One B-rep face of a CAD part: STEP entity #1964.
In plain terms, the planar face has unit normal (0, -1, 0).
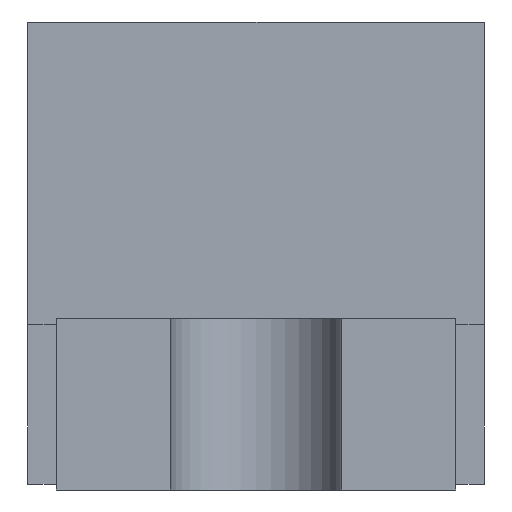
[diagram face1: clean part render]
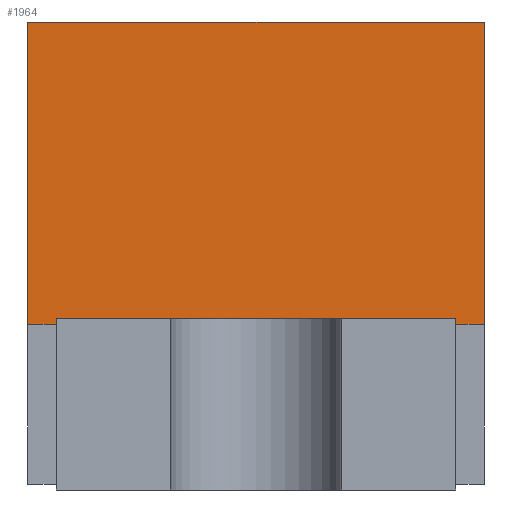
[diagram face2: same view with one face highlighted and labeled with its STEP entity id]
Its self-contained STEP definition (entity closure, numbers rounded to 3 decimals):
#1964 = ADVANCED_FACE('',(#1965),#1979,.F.);
#1965 = FACE_BOUND('',#1966,.T.);
#1966 = EDGE_LOOP('',(#1967,#2002,#2030,#2058));
#1967 = ORIENTED_EDGE('',*,*,#1968,.T.);
#1968 = EDGE_CURVE('',#1969,#1971,#1973,.T.);
#1969 = VERTEX_POINT('',#1970);
#1970 = CARTESIAN_POINT('',(110.899,-17.85,0.28));
#1971 = VERTEX_POINT('',#1972);
#1972 = CARTESIAN_POINT('',(111.699,-17.85,0.28));
#1973 = SURFACE_CURVE('',#1974,(#1978,#1990),.PCURVE_S1.);
#1974 = LINE('',#1975,#1976);
#1975 = CARTESIAN_POINT('',(111.699,-17.85,0.28));
#1976 = VECTOR('',#1977,1.);
#1977 = DIRECTION('',(1.,0.,0.));
#1978 = PCURVE('',#1979,#1984);
#1979 = PLANE('',#1980);
#1980 = AXIS2_PLACEMENT_3D('',#1981,#1982,#1983);
#1981 = CARTESIAN_POINT('',(111.699,-17.85,0.81));
#1982 = DIRECTION('',(0.,1.,0.));
#1983 = DIRECTION('',(-1.,0.,0.));
#1984 = DEFINITIONAL_REPRESENTATION('',(#1985),#1989);
#1985 = LINE('',#1986,#1987);
#1986 = CARTESIAN_POINT('',(0.,-0.53));
#1987 = VECTOR('',#1988,1.);
#1988 = DIRECTION('',(-1.,0.));
#1989 = ( GEOMETRIC_REPRESENTATION_CONTEXT(2) 
PARAMETRIC_REPRESENTATION_CONTEXT() REPRESENTATION_CONTEXT('2D SPACE',''
  ) );
#1990 = PCURVE('',#1991,#1996);
#1991 = PLANE('',#1992);
#1992 = AXIS2_PLACEMENT_3D('',#1993,#1994,#1995);
#1993 = CARTESIAN_POINT('',(111.699,-17.85,0.28));
#1994 = DIRECTION('',(0.,0.,-1.));
#1995 = DIRECTION('',(-1.,0.,0.));
#1996 = DEFINITIONAL_REPRESENTATION('',(#1997),#2001);
#1997 = LINE('',#1998,#1999);
#1998 = CARTESIAN_POINT('',(0.,0.));
#1999 = VECTOR('',#2000,1.);
#2000 = DIRECTION('',(-1.,0.));
#2001 = ( GEOMETRIC_REPRESENTATION_CONTEXT(2) 
PARAMETRIC_REPRESENTATION_CONTEXT() REPRESENTATION_CONTEXT('2D SPACE',''
  ) );
#2002 = ORIENTED_EDGE('',*,*,#2003,.F.);
#2003 = EDGE_CURVE('',#2004,#1971,#2006,.T.);
#2004 = VERTEX_POINT('',#2005);
#2005 = CARTESIAN_POINT('',(111.699,-17.85,0.81));
#2006 = SURFACE_CURVE('',#2007,(#2011,#2018),.PCURVE_S1.);
#2007 = LINE('',#2008,#2009);
#2008 = CARTESIAN_POINT('',(111.699,-17.85,0.81));
#2009 = VECTOR('',#2010,1.);
#2010 = DIRECTION('',(0.,0.,-1.));
#2011 = PCURVE('',#1979,#2012);
#2012 = DEFINITIONAL_REPRESENTATION('',(#2013),#2017);
#2013 = LINE('',#2014,#2015);
#2014 = CARTESIAN_POINT('',(0.,0.));
#2015 = VECTOR('',#2016,1.);
#2016 = DIRECTION('',(0.,-1.));
#2017 = ( GEOMETRIC_REPRESENTATION_CONTEXT(2) 
PARAMETRIC_REPRESENTATION_CONTEXT() REPRESENTATION_CONTEXT('2D SPACE',''
  ) );
#2018 = PCURVE('',#2019,#2024);
#2019 = PLANE('',#2020);
#2020 = AXIS2_PLACEMENT_3D('',#2021,#2022,#2023);
#2021 = CARTESIAN_POINT('',(111.699,-17.85,0.81));
#2022 = DIRECTION('',(-1.,0.,0.));
#2023 = DIRECTION('',(0.,-1.,0.));
#2024 = DEFINITIONAL_REPRESENTATION('',(#2025),#2029);
#2025 = LINE('',#2026,#2027);
#2026 = CARTESIAN_POINT('',(0.,0.));
#2027 = VECTOR('',#2028,1.);
#2028 = DIRECTION('',(0.,-1.));
#2029 = ( GEOMETRIC_REPRESENTATION_CONTEXT(2) 
PARAMETRIC_REPRESENTATION_CONTEXT() REPRESENTATION_CONTEXT('2D SPACE',''
  ) );
#2030 = ORIENTED_EDGE('',*,*,#2031,.F.);
#2031 = EDGE_CURVE('',#2032,#2004,#2034,.T.);
#2032 = VERTEX_POINT('',#2033);
#2033 = CARTESIAN_POINT('',(110.899,-17.85,0.81));
#2034 = SURFACE_CURVE('',#2035,(#2039,#2046),.PCURVE_S1.);
#2035 = LINE('',#2036,#2037);
#2036 = CARTESIAN_POINT('',(111.699,-17.85,0.81));
#2037 = VECTOR('',#2038,1.);
#2038 = DIRECTION('',(1.,0.,0.));
#2039 = PCURVE('',#1979,#2040);
#2040 = DEFINITIONAL_REPRESENTATION('',(#2041),#2045);
#2041 = LINE('',#2042,#2043);
#2042 = CARTESIAN_POINT('',(0.,0.));
#2043 = VECTOR('',#2044,1.);
#2044 = DIRECTION('',(-1.,0.));
#2045 = ( GEOMETRIC_REPRESENTATION_CONTEXT(2) 
PARAMETRIC_REPRESENTATION_CONTEXT() REPRESENTATION_CONTEXT('2D SPACE',''
  ) );
#2046 = PCURVE('',#2047,#2052);
#2047 = PLANE('',#2048);
#2048 = AXIS2_PLACEMENT_3D('',#2049,#2050,#2051);
#2049 = CARTESIAN_POINT('',(111.699,-17.85,0.81));
#2050 = DIRECTION('',(0.,0.,-1.));
#2051 = DIRECTION('',(-1.,0.,0.));
#2052 = DEFINITIONAL_REPRESENTATION('',(#2053),#2057);
#2053 = LINE('',#2054,#2055);
#2054 = CARTESIAN_POINT('',(0.,0.));
#2055 = VECTOR('',#2056,1.);
#2056 = DIRECTION('',(-1.,0.));
#2057 = ( GEOMETRIC_REPRESENTATION_CONTEXT(2) 
PARAMETRIC_REPRESENTATION_CONTEXT() REPRESENTATION_CONTEXT('2D SPACE',''
  ) );
#2058 = ORIENTED_EDGE('',*,*,#2059,.T.);
#2059 = EDGE_CURVE('',#2032,#1969,#2060,.T.);
#2060 = SURFACE_CURVE('',#2061,(#2065,#2072),.PCURVE_S1.);
#2061 = LINE('',#2062,#2063);
#2062 = CARTESIAN_POINT('',(110.899,-17.85,0.81));
#2063 = VECTOR('',#2064,1.);
#2064 = DIRECTION('',(0.,0.,-1.));
#2065 = PCURVE('',#1979,#2066);
#2066 = DEFINITIONAL_REPRESENTATION('',(#2067),#2071);
#2067 = LINE('',#2068,#2069);
#2068 = CARTESIAN_POINT('',(0.8,0.));
#2069 = VECTOR('',#2070,1.);
#2070 = DIRECTION('',(0.,-1.));
#2071 = ( GEOMETRIC_REPRESENTATION_CONTEXT(2) 
PARAMETRIC_REPRESENTATION_CONTEXT() REPRESENTATION_CONTEXT('2D SPACE',''
  ) );
#2072 = PCURVE('',#2073,#2078);
#2073 = PLANE('',#2074);
#2074 = AXIS2_PLACEMENT_3D('',#2075,#2076,#2077);
#2075 = CARTESIAN_POINT('',(110.899,-17.85,0.81));
#2076 = DIRECTION('',(1.,0.,0.));
#2077 = DIRECTION('',(0.,1.,0.));
#2078 = DEFINITIONAL_REPRESENTATION('',(#2079),#2083);
#2079 = LINE('',#2080,#2081);
#2080 = CARTESIAN_POINT('',(0.,0.));
#2081 = VECTOR('',#2082,1.);
#2082 = DIRECTION('',(0.,-1.));
#2083 = ( GEOMETRIC_REPRESENTATION_CONTEXT(2) 
PARAMETRIC_REPRESENTATION_CONTEXT() REPRESENTATION_CONTEXT('2D SPACE',''
  ) );
